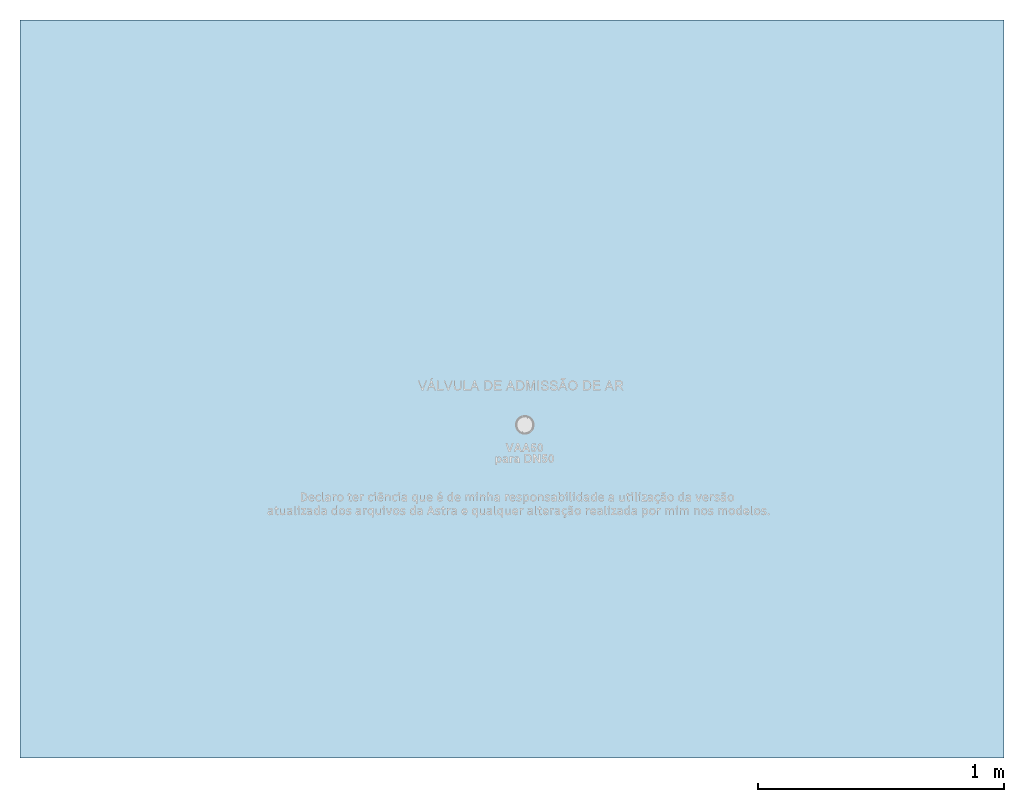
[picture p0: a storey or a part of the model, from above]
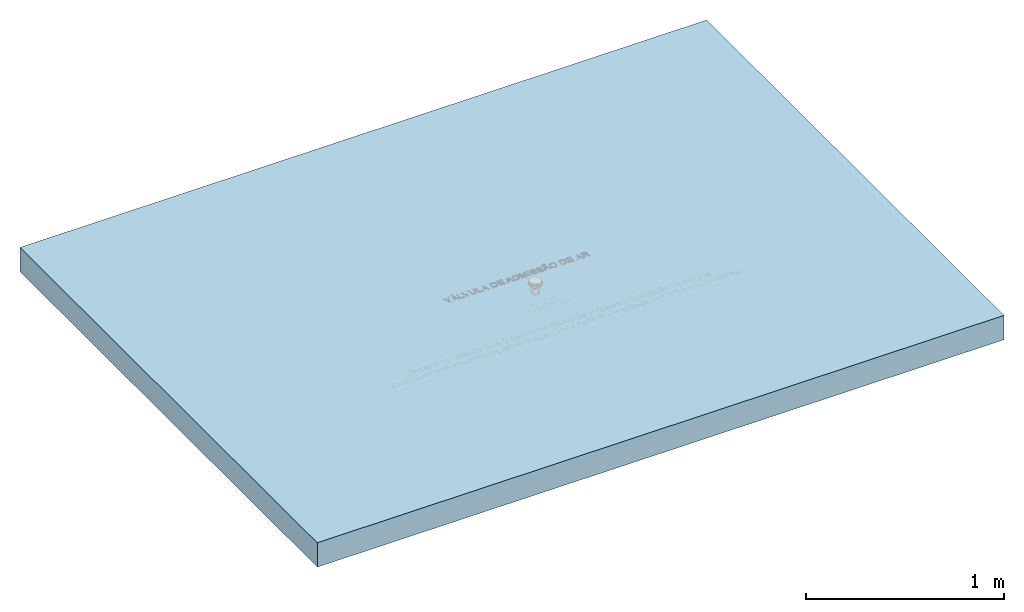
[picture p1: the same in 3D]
Properties of the parts of a building model (IFC2X3)

# File
Description: ViewDefinition [CoordinationView_V2.0]
File name: 0001
Time: 2025-07-10T16:51:18
Written by: The EXPRESS Data Manager Version 5.02.0100.07 : 28 Aug 2013
Made in: 21.0.0.383 - Exporter 21.0.0.383 - IU alternativa 21.0.0.383
Comment: STEP Physical File produced by: The EXPRESS Data Manager Version 5.02.0100.07 : 28 Aug 2013 * Module: EDMstepFileFactory/EDMstandAlone * Creation date: Thu Jul 10 16:51:18 2025 * Host: DNG1464 * Database: C:\Users\maria.cardoso\AppData\Local\Temp\09e374cc-162b-45bc-81b8-77aad4eeaad0\7123fc3c-5159-44a6-a81b-e36f13ce2fdc\ifc * Database version: 5507 * Database creation date: Thu Jul 10 16:51:13 2025 * Schema: IFC2X3 * Model: DataRepository.ifc * Model creation date: Thu Jul 10 16:51:13 2025 * Header model: DataRepository.ifc_HeaderModel * Header model creation date: Thu Jul 10 16:51:13 2025 * EDMuser: sdai-user * EDMgroup: sdai-group * License ID and type: 5605 : Permanent license. Expiry date: * EDMstepFileFactory options: 020000

# IfcProject, 0001
LongName: Nome do projeto; Phase: Status do projeto

# IfcSite, Default
RefLatitude: -15, -52, 0, -120620; RefLongitude: -47, -55, 0, -114440; RefElevation: 0 mm

# IfcBuilding
Pset_BuildingCommon - NumberOfStoreys: 1

# IfcBuildingStorey: Nível:Cabeça de 8 mm, Vista Principal
LongName: Vista Principal; Elevation: 0 mm

# IfcBuildingElementProxy: Texto do modelo:600mm Arial, Texto do modelo:600mm Arial:338745
In: Vista Principal
Type - Pset_BuildingElementProxyCommon - Reference: 600mm Arial
Type - Pset_QuantityTakeOff - Reference: 600mm Arial
Pset_BuildingElementProxyCommon - sets with these values: 2

# IfcBuildingElementProxy: Texto do modelo:600mm Arial 2, Texto do modelo:600mm Arial 2:338741
In: Vista Principal
Type - Pset_BuildingElementProxyCommon - Reference: 600mm Arial 2
Type - Pset_QuantityTakeOff - Reference: 600mm Arial 2
Pset_BuildingElementProxyCommon - sets with these values: 2

# IfcBuildingElementProxy: Texto do modelo:TITULO, Texto do modelo:TITULO:338921
In: Vista Principal
Type - Pset_BuildingElementProxyCommon - Reference: TITULO
Type - Pset_QuantityTakeOff - Reference: TITULO
Pset_BuildingElementProxyCommon - sets with these values: 2

# IfcDistributionPort, Port_344303
Description: Flow; FlowDirection: SOURCEANDSINK

# IfcFlowController: VAA50:Válvula de Admissão de Ar - Astra, VAA50:Válvula de Admissão de Ar - Astra:344303
In: Vista Principal
Type - Pset_DistributionFlowElementCommon - Reference: Válvula de Admissão de Ar - Astra
Type - Pset_ManufacturerTypeInformation - Manufacturer: Astra
Type - Pset_QuantityTakeOff - Reference: Válvula de Admissão de Ar - Astra
Pset_DistributionFlowElementCommon - sets with these values: 2

# IfcSlab: Piso:Genérico 150 mm, Piso:Genérico 150 mm:330359
In: Vista Principal
Type - PredefinedType: FLOOR; Material: Material pré-definido de piso 150 mm
Type - Pset_QuantityTakeOff - Reference: Genérico 150 mm
Type - Pset_ReinforcementBarPitchOfSlab - Reference: Genérico 150 mm
Type - Pset_SlabCommon - Reference: Genérico 150 mm; IsExternal: no
Pset_QuantityTakeOff - sets with these values: 2
Pset_SlabCommon - LoadBearing: no; PitchAngle: 0 deg
